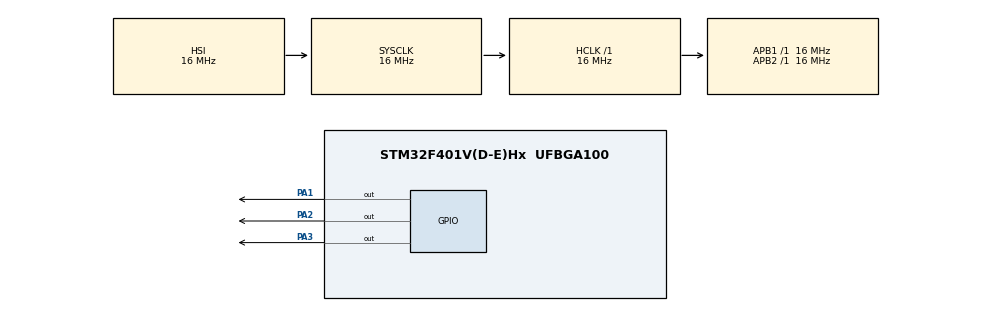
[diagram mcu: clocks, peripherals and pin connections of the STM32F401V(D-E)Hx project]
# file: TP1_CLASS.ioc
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Mcu.Family=STM32F4
Mcu.Name=STM32F401V(D-E)Hx
Mcu.Package=UFBGA100
NVIC.PriorityGroup=NVIC_PRIORITYGROUP_4
PA1.Signal=GPIO_Output
PA2.Signal=GPIO_Output
PA3.Signal=GPIO_Output
ProjectManager.HeapSize=0x200
ProjectManager.StackSize=0x400
ProjectManager.TargetToolchain=STM32CubeIDE
RCC.AHBFreq_Value=16000000
RCC.APB1Freq_Value=16000000
RCC.APB1TimFreq_Value=16000000
RCC.APB2Freq_Value=16000000
RCC.APB2TimFreq_Value=16000000
RCC.CortexFreq_Value=16000000
RCC.HCLKFreq_Value=16000000
RCC.HSE_VALUE=25000000
RCC.HSI_VALUE=16000000
RCC.LSE_VALUE=32768
RCC.SYSCLKFreq_VALUE=16000000
RCC.VCOOutputFreq_Value=192000000
board=custom

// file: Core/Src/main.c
#include "main.h"

void SystemClock_Config(void);
static void MX_GPIO_Init(void);

char value[10] ={0x3f,0x06,0x5b,0x4f,0x66,0x6d,0x7d,0x07,0x7f,0x6f};
//char value[10] ={63,6,91,79,102,109,125,7,127,111}

int main(void)
{
  /* USER CODE BEGIN 1 */

  HAL_Init();
  SystemClock_Config();
  MX_GPIO_Init();

  while (1)
  {

	  short i;
	  	for(i=0;i<10;i++)
	  		{
	  			HAL_GPIO_WritePin(GPIOD, value[i], GPIO_PIN_SET);
	  			HAL_Delay(300);
	  			HAL_GPIO_WritePin(GPIOD,value[i], GPIO_PIN_RESET);
	  		}

	    /*  short i;
	for(i=1;i<7;i++)
	{
		HAL_GPIO_WritePin(GPIOA, 1<<i, GPIO_PIN_SET);
		HAL_Delay(300);
		HAL_GPIO_WritePin(GPIOA,1<<i, GPIO_PIN_RESET);
	}
*/
  }

}

void SystemClock_Config(void)
{
  RCC_OscInitTypeDef RCC_OscInitStruct = {0};
  RCC_ClkInitTypeDef RCC_ClkInitStruct = {0};

  /** Configure the main internal regulator output voltage
  */
  __HAL_RCC_PWR_CLK_ENABLE();
  __HAL_PWR_VOLTAGESCALING_CONFIG(PWR_REGULATOR_VOLTAGE_SCALE2);

  /** Initializes the RCC Oscillators according to the specified parameters
  * in the RCC_OscInitTypeDef structure.
  */
  RCC_OscInitStruct.OscillatorType = RCC_OSCILLATORTYPE_HSI;
  RCC_OscInitStruct.HSIState = RCC_HSI_ON;
  RCC_OscInitStruct.HSICalibrationValue = RCC_HSICALIBRATION_DEFAULT;
  RCC_OscInitStruct.PLL.PLLState = RCC_PLL_NONE;
  if (HAL_RCC_OscConfig(&RCC_OscInitStruct) != HAL_OK)
  {
    Error_Handler();
  }

  /** Initializes the CPU, AHB and APB buses clocks
  */
  RCC_ClkInitStruct.ClockType = RCC_CLOCKTYPE_HCLK|RCC_CLOCKTYPE_SYSCLK
                              |RCC_CLOCKTYPE_PCLK1|RCC_CLOCKTYPE_PCLK2;
  RCC_ClkInitStruct.SYSCLKSource = RCC_SYSCLKSOURCE_HSI;
  RCC_ClkInitStruct.AHBCLKDivider = RCC_SYSCLK_DIV1;
  RCC_ClkInitStruct.APB1CLKDivider = RCC_HCLK_DIV1;
  RCC_ClkInitStruct.APB2CLKDivider = RCC_HCLK_DIV1;

  if (HAL_RCC_ClockConfig(&RCC_ClkInitStruct, FLASH_LATENCY_0) != HAL_OK)
  {
    Error_Handler();
  }
}

static void MX_GPIO_Init(void)
{
  GPIO_InitTypeDef GPIO_InitStruct = {0};

  /* GPIO Ports Clock Enable */
  __HAL_RCC_GPIOA_CLK_ENABLE(); // activation d'horloge port A pour  les leds
  __HAL_RCC_GPIOD_CLK_ENABLE(); // activation d'horloge port d pour 7 seg

  /*Configure GPIO pin Output Level */
  HAL_GPIO_WritePin(GPIOA, GPIO_PIN_2|GPIO_PIN_3|GPIO_PIN_1, GPIO_PIN_RESET);

  /*Configure GPIO pins : PA2 PA3 PA1  */
  // partie du port A
  GPIO_InitStruct.Pin = GPIO_PIN_2|GPIO_PIN_3|GPIO_PIN_1|GPIO_PIN_4|GPIO_PIN_5|GPIO_PIN_6;
  GPIO_InitStruct.Mode = GPIO_MODE_OUTPUT_PP;
  GPIO_InitStruct.Pull = GPIO_NOPULL;
  GPIO_InitStruct.Speed = GPIO_SPEED_FREQ_LOW;
  HAL_GPIO_Init(GPIOA, &GPIO_InitStruct);

  // partie du port D pour 7 seg
  GPIO_InitStruct.Pin = GPIO_PIN_0|GPIO_PIN_1|GPIO_PIN_2|GPIO_PIN_3|GPIO_PIN_4|GPIO_PIN_5|GPIO_PIN_6;
  GPIO_InitStruct.Mode = GPIO_MODE_OUTPUT_PP;
  GPIO_InitStruct.Pull = GPIO_NOPULL;
  GPIO_InitStruct.Speed = GPIO_SPEED_FREQ_LOW;
  HAL_GPIO_Init(GPIOD, &GPIO_InitStruct);
/*  for(int i=0;i<7;i++)
  {
	  	 GPIO_InitStruct.Pin = 1<<i;
  	    GPIO_InitStruct.Mode = GPIO_MODE_OUTPUT_PP;
  	    GPIO_InitStruct.Pull = GPIO_NOPULL;
  	    GPIO_InitStruct.Speed = GPIO_SPEED_FREQ_LOW;
  	    HAL_GPIO_Init(GPIOD, &GPIO_InitStruct);

  }*/
}

void Error_Handler(void)
{

  __disable_irq();
  while (1)
  {
  }
  /* USER CODE END Error_Handler_Debug */
}
